###############################################################
#  Generated by:      Cadence Innovus 23.14-s088_1
#  OS:                Linux x86_64(Host ID user1-EliteMini)
#  Generated on:      Wed Aug 12 00:47:21 2026
#  Design:            riscv_pipeline
#  Command:           write_lef_abstract -noCutObs ./outputs/riscv_pipeline.lef
###############################################################

VERSION 5.8 ;

BUSBITCHARS "[]" ;
DIVIDERCHAR "/" ;

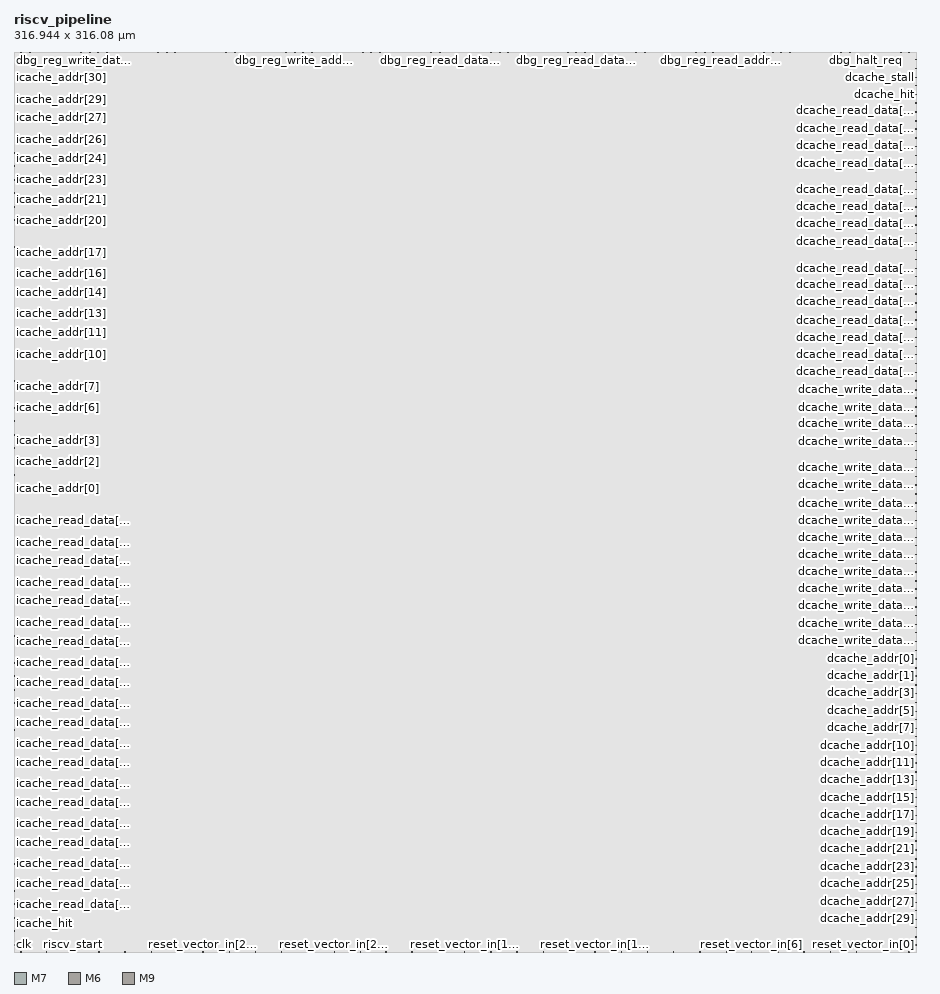
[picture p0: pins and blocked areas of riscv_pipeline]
MACRO riscv_pipeline
  CLASS BLOCK ;
  SIZE 316.944000 BY 316.080000 ;
  FOREIGN riscv_pipeline 0.000000 0.000000 ;
  ORIGIN 0 0 ;
  SYMMETRY X Y R90 ;
  PIN clk
    DIRECTION INPUT ;
    USE SIGNAL ;
    PORT
      LAYER M7 ;
        RECT 2.384000 0.000000 2.512000 0.288000 ;
    END
  END clk
  PIN reset_n
    DIRECTION INPUT ;
    USE SIGNAL ;
    PORT
      LAYER M7 ;
        RECT 11.312000 0.000000 11.440000 0.288000 ;
    END
  END reset_n
  PIN riscv_start
    DIRECTION INPUT ;
    USE SIGNAL ;
    PORT
      LAYER M7 ;
        RECT 20.528000 0.000000 20.656000 0.288000 ;
    END
  END riscv_start
  PIN meip_i
    DIRECTION INPUT ;
    USE SIGNAL ;
    PORT
      LAYER M7 ;
        RECT 314.288000 315.792000 314.416000 316.080000 ;
    END
  END meip_i
  PIN msip_i
    DIRECTION INPUT ;
    USE SIGNAL ;
    PORT
      LAYER M7 ;
        RECT 311.408000 315.792000 311.536000 316.080000 ;
    END
  END msip_i
  PIN mtip_i
    DIRECTION INPUT ;
    USE SIGNAL ;
    PORT
      LAYER M7 ;
        RECT 308.528000 315.792000 308.656000 316.080000 ;
    END
  END mtip_i
  PIN reset_vector_in[31]
    DIRECTION INPUT ;
    USE SIGNAL ;
    PORT
      LAYER M7 ;
        RECT 29.744000 0.000000 29.872000 0.288000 ;
    END
  END reset_vector_in[31]
  PIN reset_vector_in[30]
    DIRECTION INPUT ;
    USE SIGNAL ;
    PORT
      LAYER M7 ;
        RECT 38.960000 0.000000 39.088000 0.288000 ;
    END
  END reset_vector_in[30]
  PIN reset_vector_in[29]
    DIRECTION INPUT ;
    USE SIGNAL ;
    PORT
      LAYER M7 ;
        RECT 48.176000 0.000000 48.304000 0.288000 ;
    END
  END reset_vector_in[29]
  PIN reset_vector_in[28]
    DIRECTION INPUT ;
    USE SIGNAL ;
    PORT
      LAYER M7 ;
        RECT 57.392000 0.000000 57.520000 0.288000 ;
    END
  END reset_vector_in[28]
  PIN reset_vector_in[27]
    DIRECTION INPUT ;
    USE SIGNAL ;
    PORT
      LAYER M7 ;
        RECT 66.320000 0.000000 66.448000 0.288000 ;
    END
  END reset_vector_in[27]
  PIN reset_vector_in[26]
    DIRECTION INPUT ;
    USE SIGNAL ;
    PORT
      LAYER M7 ;
        RECT 75.536000 0.000000 75.664000 0.288000 ;
    END
  END reset_vector_in[26]
  PIN reset_vector_in[25]
    DIRECTION INPUT ;
    USE SIGNAL ;
    PORT
      LAYER M7 ;
        RECT 84.752000 0.000000 84.880000 0.288000 ;
    END
  END reset_vector_in[25]
  PIN reset_vector_in[24]
    DIRECTION INPUT ;
    USE SIGNAL ;
    PORT
      LAYER M7 ;
        RECT 93.968000 0.000000 94.096000 0.288000 ;
    END
  END reset_vector_in[24]
  PIN reset_vector_in[23]
    DIRECTION INPUT ;
    USE SIGNAL ;
    PORT
      LAYER M7 ;
        RECT 103.184000 0.000000 103.312000 0.288000 ;
    END
  END reset_vector_in[23]
  PIN reset_vector_in[22]
    DIRECTION INPUT ;
    USE SIGNAL ;
    PORT
      LAYER M7 ;
        RECT 112.400000 0.000000 112.528000 0.288000 ;
    END
  END reset_vector_in[22]
  PIN reset_vector_in[21]
    DIRECTION INPUT ;
    USE SIGNAL ;
    PORT
      LAYER M7 ;
        RECT 121.616000 0.000000 121.744000 0.288000 ;
    END
  END reset_vector_in[21]
  PIN reset_vector_in[20]
    DIRECTION INPUT ;
    USE SIGNAL ;
    PORT
      LAYER M7 ;
        RECT 130.544000 0.000000 130.672000 0.288000 ;
    END
  END reset_vector_in[20]
  PIN reset_vector_in[19]
    DIRECTION INPUT ;
    USE SIGNAL ;
    PORT
      LAYER M7 ;
        RECT 139.760000 0.000000 139.888000 0.288000 ;
    END
  END reset_vector_in[19]
  PIN reset_vector_in[18]
    DIRECTION INPUT ;
    USE SIGNAL ;
    PORT
      LAYER M7 ;
        RECT 148.976000 0.000000 149.104000 0.288000 ;
    END
  END reset_vector_in[18]
  PIN reset_vector_in[17]
    DIRECTION INPUT ;
    USE SIGNAL ;
    PORT
      LAYER M7 ;
        RECT 158.192000 0.000000 158.320000 0.288000 ;
    END
  END reset_vector_in[17]
  PIN reset_vector_in[16]
    DIRECTION INPUT ;
    USE SIGNAL ;
    PORT
      LAYER M7 ;
        RECT 167.408000 0.000000 167.536000 0.288000 ;
    END
  END reset_vector_in[16]
  PIN reset_vector_in[15]
    DIRECTION INPUT ;
    USE SIGNAL ;
    PORT
      LAYER M7 ;
        RECT 176.624000 0.000000 176.752000 0.288000 ;
    END
  END reset_vector_in[15]
  PIN reset_vector_in[14]
    DIRECTION INPUT ;
    USE SIGNAL ;
    PORT
      LAYER M7 ;
        RECT 185.840000 0.000000 185.968000 0.288000 ;
    END
  END reset_vector_in[14]
  PIN reset_vector_in[13]
    DIRECTION INPUT ;
    USE SIGNAL ;
    PORT
      LAYER M7 ;
        RECT 194.768000 0.000000 194.896000 0.288000 ;
    END
  END reset_vector_in[13]
  PIN reset_vector_in[12]
    DIRECTION INPUT ;
    USE SIGNAL ;
    PORT
      LAYER M7 ;
        RECT 203.984000 0.000000 204.112000 0.288000 ;
    END
  END reset_vector_in[12]
  PIN reset_vector_in[11]
    DIRECTION INPUT ;
    USE SIGNAL ;
    PORT
      LAYER M7 ;
        RECT 213.200000 0.000000 213.328000 0.288000 ;
    END
  END reset_vector_in[11]
  PIN reset_vector_in[10]
    DIRECTION INPUT ;
    USE SIGNAL ;
    PORT
      LAYER M7 ;
        RECT 222.416000 0.000000 222.544000 0.288000 ;
    END
  END reset_vector_in[10]
  PIN reset_vector_in[9]
    DIRECTION INPUT ;
    USE SIGNAL ;
    PORT
      LAYER M7 ;
        RECT 231.632000 0.000000 231.760000 0.288000 ;
    END
  END reset_vector_in[9]
  PIN reset_vector_in[8]
    DIRECTION INPUT ;
    USE SIGNAL ;
    PORT
      LAYER M7 ;
        RECT 240.848000 0.000000 240.976000 0.288000 ;
    END
  END reset_vector_in[8]
  PIN reset_vector_in[7]
    DIRECTION INPUT ;
    USE SIGNAL ;
    PORT
      LAYER M7 ;
        RECT 250.064000 0.000000 250.192000 0.288000 ;
    END
  END reset_vector_in[7]
  PIN reset_vector_in[6]
    DIRECTION INPUT ;
    USE SIGNAL ;
    PORT
      LAYER M7 ;
        RECT 258.992000 0.000000 259.120000 0.288000 ;
    END
  END reset_vector_in[6]
  PIN reset_vector_in[5]
    DIRECTION INPUT ;
    USE SIGNAL ;
    PORT
      LAYER M7 ;
        RECT 268.208000 0.000000 268.336000 0.288000 ;
    END
  END reset_vector_in[5]
  PIN reset_vector_in[4]
    DIRECTION INPUT ;
    USE SIGNAL ;
    PORT
      LAYER M7 ;
        RECT 277.424000 0.000000 277.552000 0.288000 ;
    END
  END reset_vector_in[4]
  PIN reset_vector_in[3]
    DIRECTION INPUT ;
    USE SIGNAL ;
    PORT
      LAYER M7 ;
        RECT 286.640000 0.000000 286.768000 0.288000 ;
    END
  END reset_vector_in[3]
  PIN reset_vector_in[2]
    DIRECTION INPUT ;
    USE SIGNAL ;
    PORT
      LAYER M7 ;
        RECT 295.856000 0.000000 295.984000 0.288000 ;
    END
  END reset_vector_in[2]
  PIN reset_vector_in[1]
    DIRECTION INPUT ;
    USE SIGNAL ;
    PORT
      LAYER M7 ;
        RECT 305.072000 0.000000 305.200000 0.288000 ;
    END
  END reset_vector_in[1]
  PIN reset_vector_in[0]
    DIRECTION INPUT ;
    USE SIGNAL ;
    PORT
      LAYER M7 ;
        RECT 314.288000 0.000000 314.416000 0.288000 ;
    END
  END reset_vector_in[0]
  PIN riscv_done
    DIRECTION OUTPUT ;
    USE SIGNAL ;
    PORT
      LAYER M7 ;
        RECT 305.360000 315.792000 305.488000 316.080000 ;
    END
  END riscv_done
  PIN icache_read_req
    DIRECTION OUTPUT ;
    USE SIGNAL ;
    PORT
      LAYER M6 ;
        RECT 0.000000 313.424000 0.288000 313.552000 ;
    END
  END icache_read_req
  PIN icache_addr[31]
    DIRECTION OUTPUT ;
    USE SIGNAL ;
    PORT
      LAYER M6 ;
        RECT 0.000000 308.816000 0.288000 308.944000 ;
    END
  END icache_addr[31]
  PIN icache_addr[30]
    DIRECTION OUTPUT ;
    USE SIGNAL ;
    PORT
      LAYER M6 ;
        RECT 0.000000 304.208000 0.288000 304.336000 ;
    END
  END icache_addr[30]
  PIN icache_addr[29]
    DIRECTION OUTPUT ;
    USE SIGNAL ;
    PORT
      LAYER M6 ;
        RECT 0.000000 299.312000 0.288000 299.440000 ;
    END
  END icache_addr[29]
  PIN icache_addr[28]
    DIRECTION OUTPUT ;
    USE SIGNAL ;
    PORT
      LAYER M6 ;
        RECT 0.000000 294.704000 0.288000 294.832000 ;
    END
  END icache_addr[28]
  PIN icache_addr[27]
    DIRECTION OUTPUT ;
    USE SIGNAL ;
    PORT
      LAYER M6 ;
        RECT 0.000000 290.096000 0.288000 290.224000 ;
    END
  END icache_addr[27]
  PIN icache_addr[26]
    DIRECTION OUTPUT ;
    USE SIGNAL ;
    PORT
      LAYER M6 ;
        RECT 0.000000 285.200000 0.288000 285.328000 ;
    END
  END icache_addr[26]
  PIN icache_addr[25]
    DIRECTION OUTPUT ;
    USE SIGNAL ;
    PORT
      LAYER M6 ;
        RECT 0.000000 280.592000 0.288000 280.720000 ;
    END
  END icache_addr[25]
  PIN icache_addr[24]
    DIRECTION OUTPUT ;
    USE SIGNAL ;
    PORT
      LAYER M6 ;
        RECT 0.000000 275.984000 0.288000 276.112000 ;
    END
  END icache_addr[24]
  PIN icache_addr[23]
    DIRECTION OUTPUT ;
    USE SIGNAL ;
    PORT
      LAYER M6 ;
        RECT 0.000000 271.088000 0.288000 271.216000 ;
    END
  END icache_addr[23]
  PIN icache_addr[22]
    DIRECTION OUTPUT ;
    USE SIGNAL ;
    PORT
      LAYER M6 ;
        RECT 0.000000 266.480000 0.288000 266.608000 ;
    END
  END icache_addr[22]
  PIN icache_addr[21]
    DIRECTION OUTPUT ;
    USE SIGNAL ;
    PORT
      LAYER M6 ;
        RECT 0.000000 261.584000 0.288000 261.712000 ;
    END
  END icache_addr[21]
  PIN icache_addr[20]
    DIRECTION OUTPUT ;
    USE SIGNAL ;
    PORT
      LAYER M6 ;
        RECT 0.000000 256.976000 0.288000 257.104000 ;
    END
  END icache_addr[20]
  PIN icache_addr[19]
    DIRECTION OUTPUT ;
    USE SIGNAL ;
    PORT
      LAYER M6 ;
        RECT 0.000000 252.368000 0.288000 252.496000 ;
    END
  END icache_addr[19]
  PIN icache_addr[18]
    DIRECTION OUTPUT ;
    USE SIGNAL ;
    PORT
      LAYER M6 ;
        RECT 0.000000 247.472000 0.288000 247.600000 ;
    END
  END icache_addr[18]
  PIN icache_addr[17]
    DIRECTION OUTPUT ;
    USE SIGNAL ;
    PORT
      LAYER M6 ;
        RECT 0.000000 242.864000 0.288000 242.992000 ;
    END
  END icache_addr[17]
  PIN icache_addr[16]
    DIRECTION OUTPUT ;
    USE SIGNAL ;
    PORT
      LAYER M6 ;
        RECT 0.000000 238.256000 0.288000 238.384000 ;
    END
  END icache_addr[16]
  PIN icache_addr[15]
    DIRECTION OUTPUT ;
    USE SIGNAL ;
    PORT
      LAYER M6 ;
        RECT 0.000000 233.360000 0.288000 233.488000 ;
    END
  END icache_addr[15]
  PIN icache_addr[14]
    DIRECTION OUTPUT ;
    USE SIGNAL ;
    PORT
      LAYER M6 ;
        RECT 0.000000 228.752000 0.288000 228.880000 ;
    END
  END icache_addr[14]
  PIN icache_addr[13]
    DIRECTION OUTPUT ;
    USE SIGNAL ;
    PORT
      LAYER M6 ;
        RECT 0.000000 224.144000 0.288000 224.272000 ;
    END
  END icache_addr[13]
  PIN icache_addr[12]
    DIRECTION OUTPUT ;
    USE SIGNAL ;
    PORT
      LAYER M6 ;
        RECT 0.000000 219.248000 0.288000 219.376000 ;
    END
  END icache_addr[12]
  PIN icache_addr[11]
    DIRECTION OUTPUT ;
    USE SIGNAL ;
    PORT
      LAYER M6 ;
        RECT 0.000000 214.640000 0.288000 214.768000 ;
    END
  END icache_addr[11]
  PIN icache_addr[10]
    DIRECTION OUTPUT ;
    USE SIGNAL ;
    PORT
      LAYER M6 ;
        RECT 0.000000 209.744000 0.288000 209.872000 ;
    END
  END icache_addr[10]
  PIN icache_addr[9]
    DIRECTION OUTPUT ;
    USE SIGNAL ;
    PORT
      LAYER M6 ;
        RECT 0.000000 205.136000 0.288000 205.264000 ;
    END
  END icache_addr[9]
  PIN icache_addr[8]
    DIRECTION OUTPUT ;
    USE SIGNAL ;
    PORT
      LAYER M6 ;
        RECT 0.000000 200.528000 0.288000 200.656000 ;
    END
  END icache_addr[8]
  PIN icache_addr[7]
    DIRECTION OUTPUT ;
    USE SIGNAL ;
    PORT
      LAYER M6 ;
        RECT 0.000000 195.632000 0.288000 195.760000 ;
    END
  END icache_addr[7]
  PIN icache_addr[6]
    DIRECTION OUTPUT ;
    USE SIGNAL ;
    PORT
      LAYER M6 ;
        RECT 0.000000 191.024000 0.288000 191.152000 ;
    END
  END icache_addr[6]
  PIN icache_addr[5]
    DIRECTION OUTPUT ;
    USE SIGNAL ;
    PORT
      LAYER M6 ;
        RECT 0.000000 186.416000 0.288000 186.544000 ;
    END
  END icache_addr[5]
  PIN icache_addr[4]
    DIRECTION OUTPUT ;
    USE SIGNAL ;
    PORT
      LAYER M6 ;
        RECT 0.000000 181.520000 0.288000 181.648000 ;
    END
  END icache_addr[4]
  PIN icache_addr[3]
    DIRECTION OUTPUT ;
    USE SIGNAL ;
    PORT
      LAYER M6 ;
        RECT 0.000000 176.912000 0.288000 177.040000 ;
    END
  END icache_addr[3]
  PIN icache_addr[2]
    DIRECTION OUTPUT ;
    USE SIGNAL ;
    PORT
      LAYER M6 ;
        RECT 0.000000 172.304000 0.288000 172.432000 ;
    END
  END icache_addr[2]
  PIN icache_addr[1]
    DIRECTION OUTPUT ;
    USE SIGNAL ;
    PORT
      LAYER M6 ;
        RECT 0.000000 167.408000 0.288000 167.536000 ;
    END
  END icache_addr[1]
  PIN icache_addr[0]
    DIRECTION OUTPUT ;
    USE SIGNAL ;
    PORT
      LAYER M6 ;
        RECT 0.000000 162.800000 0.288000 162.928000 ;
    END
  END icache_addr[0]
  PIN icache_read_data[31]
    DIRECTION INPUT ;
    USE SIGNAL ;
    PORT
      LAYER M6 ;
        RECT 0.000000 157.904000 0.288000 158.032000 ;
    END
  END icache_read_data[31]
  PIN icache_read_data[30]
    DIRECTION INPUT ;
    USE SIGNAL ;
    PORT
      LAYER M6 ;
        RECT 0.000000 153.296000 0.288000 153.424000 ;
    END
  END icache_read_data[30]
  PIN icache_read_data[29]
    DIRECTION INPUT ;
    USE SIGNAL ;
    PORT
      LAYER M6 ;
        RECT 0.000000 148.688000 0.288000 148.816000 ;
    END
  END icache_read_data[29]
  PIN icache_read_data[28]
    DIRECTION INPUT ;
    USE SIGNAL ;
    PORT
      LAYER M6 ;
        RECT 0.000000 143.792000 0.288000 143.920000 ;
    END
  END icache_read_data[28]
  PIN icache_read_data[27]
    DIRECTION INPUT ;
    USE SIGNAL ;
    PORT
      LAYER M6 ;
        RECT 0.000000 139.184000 0.288000 139.312000 ;
    END
  END icache_read_data[27]
  PIN icache_read_data[26]
    DIRECTION INPUT ;
    USE SIGNAL ;
    PORT
      LAYER M6 ;
        RECT 0.000000 134.576000 0.288000 134.704000 ;
    END
  END icache_read_data[26]
  PIN icache_read_data[25]
    DIRECTION INPUT ;
    USE SIGNAL ;
    PORT
      LAYER M6 ;
        RECT 0.000000 129.680000 0.288000 129.808000 ;
    END
  END icache_read_data[25]
  PIN icache_read_data[24]
    DIRECTION INPUT ;
    USE SIGNAL ;
    PORT
      LAYER M6 ;
        RECT 0.000000 125.072000 0.288000 125.200000 ;
    END
  END icache_read_data[24]
  PIN icache_read_data[23]
    DIRECTION INPUT ;
    USE SIGNAL ;
    PORT
      LAYER M6 ;
        RECT 0.000000 120.464000 0.288000 120.592000 ;
    END
  END icache_read_data[23]
  PIN icache_read_data[22]
    DIRECTION INPUT ;
    USE SIGNAL ;
    PORT
      LAYER M6 ;
        RECT 0.000000 115.568000 0.288000 115.696000 ;
    END
  END icache_read_data[22]
  PIN icache_read_data[21]
    DIRECTION INPUT ;
    USE SIGNAL ;
    PORT
      LAYER M6 ;
        RECT 0.000000 110.960000 0.288000 111.088000 ;
    END
  END icache_read_data[21]
  PIN icache_read_data[20]
    DIRECTION INPUT ;
    USE SIGNAL ;
    PORT
      LAYER M6 ;
        RECT 0.000000 106.064000 0.288000 106.192000 ;
    END
  END icache_read_data[20]
  PIN icache_read_data[19]
    DIRECTION INPUT ;
    USE SIGNAL ;
    PORT
      LAYER M6 ;
        RECT 0.000000 101.456000 0.288000 101.584000 ;
    END
  END icache_read_data[19]
  PIN icache_read_data[18]
    DIRECTION INPUT ;
    USE SIGNAL ;
    PORT
      LAYER M6 ;
        RECT 0.000000 96.848000 0.288000 96.976000 ;
    END
  END icache_read_data[18]
  PIN icache_read_data[17]
    DIRECTION INPUT ;
    USE SIGNAL ;
    PORT
      LAYER M6 ;
        RECT 0.000000 91.952000 0.288000 92.080000 ;
    END
  END icache_read_data[17]
  PIN icache_read_data[16]
    DIRECTION INPUT ;
    USE SIGNAL ;
    PORT
      LAYER M6 ;
        RECT 0.000000 87.344000 0.288000 87.472000 ;
    END
  END icache_read_data[16]
  PIN icache_read_data[15]
    DIRECTION INPUT ;
    USE SIGNAL ;
    PORT
      LAYER M6 ;
        RECT 0.000000 82.736000 0.288000 82.864000 ;
    END
  END icache_read_data[15]
  PIN icache_read_data[14]
    DIRECTION INPUT ;
    USE SIGNAL ;
    PORT
      LAYER M6 ;
        RECT 0.000000 77.840000 0.288000 77.968000 ;
    END
  END icache_read_data[14]
  PIN icache_read_data[13]
    DIRECTION INPUT ;
    USE SIGNAL ;
    PORT
      LAYER M6 ;
        RECT 0.000000 73.232000 0.288000 73.360000 ;
    END
  END icache_read_data[13]
  PIN icache_read_data[12]
    DIRECTION INPUT ;
    USE SIGNAL ;
    PORT
      LAYER M6 ;
        RECT 0.000000 68.624000 0.288000 68.752000 ;
    END
  END icache_read_data[12]
  PIN icache_read_data[11]
    DIRECTION INPUT ;
    USE SIGNAL ;
    PORT
      LAYER M6 ;
        RECT 0.000000 63.728000 0.288000 63.856000 ;
    END
  END icache_read_data[11]
  PIN icache_read_data[10]
    DIRECTION INPUT ;
    USE SIGNAL ;
    PORT
      LAYER M6 ;
        RECT 0.000000 59.120000 0.288000 59.248000 ;
    END
  END icache_read_data[10]
  PIN icache_read_data[9]
    DIRECTION INPUT ;
    USE SIGNAL ;
    PORT
      LAYER M6 ;
        RECT 0.000000 54.224000 0.288000 54.352000 ;
    END
  END icache_read_data[9]
  PIN icache_read_data[8]
    DIRECTION INPUT ;
    USE SIGNAL ;
    PORT
      LAYER M6 ;
        RECT 0.000000 49.616000 0.288000 49.744000 ;
    END
  END icache_read_data[8]
  PIN icache_read_data[7]
    DIRECTION INPUT ;
    USE SIGNAL ;
    PORT
      LAYER M6 ;
        RECT 0.000000 45.008000 0.288000 45.136000 ;
    END
  END icache_read_data[7]
  PIN icache_read_data[6]
    DIRECTION INPUT ;
    USE SIGNAL ;
    PORT
      LAYER M6 ;
        RECT 0.000000 40.112000 0.288000 40.240000 ;
    END
  END icache_read_data[6]
  PIN icache_read_data[5]
    DIRECTION INPUT ;
    USE SIGNAL ;
    PORT
      LAYER M6 ;
        RECT 0.000000 35.504000 0.288000 35.632000 ;
    END
  END icache_read_data[5]
  PIN icache_read_data[4]
    DIRECTION INPUT ;
    USE SIGNAL ;
    PORT
      LAYER M6 ;
        RECT 0.000000 30.896000 0.288000 31.024000 ;
    END
  END icache_read_data[4]
  PIN icache_read_data[3]
    DIRECTION INPUT ;
    USE SIGNAL ;
    PORT
      LAYER M6 ;
        RECT 0.000000 26.000000 0.288000 26.128000 ;
    END
  END icache_read_data[3]
  PIN icache_read_data[2]
    DIRECTION INPUT ;
    USE SIGNAL ;
    PORT
      LAYER M6 ;
        RECT 0.000000 21.392000 0.288000 21.520000 ;
    END
  END icache_read_data[2]
  PIN icache_read_data[1]
    DIRECTION INPUT ;
    USE SIGNAL ;
    PORT
      LAYER M6 ;
        RECT 0.000000 16.784000 0.288000 16.912000 ;
    END
  END icache_read_data[1]
  PIN icache_read_data[0]
    DIRECTION INPUT ;
    USE SIGNAL ;
    PORT
      LAYER M6 ;
        RECT 0.000000 11.888000 0.288000 12.016000 ;
    END
  END icache_read_data[0]
  PIN icache_hit
    DIRECTION INPUT ;
    USE SIGNAL ;
    PORT
      LAYER M6 ;
        RECT 0.000000 7.280000 0.288000 7.408000 ;
    END
  END icache_hit
  PIN icache_stall
    DIRECTION INPUT ;
    USE SIGNAL ;
    PORT
      LAYER M6 ;
        RECT 0.000000 2.384000 0.288000 2.512000 ;
    END
  END icache_stall
  PIN dcache_read_req
    DIRECTION OUTPUT ;
    USE SIGNAL ;
    PORT
      LAYER M6 ;
        RECT 316.656000 2.384000 316.944000 2.512000 ;
    END
  END dcache_read_req
  PIN dcache_write_req
    DIRECTION OUTPUT ;
    USE SIGNAL ;
    PORT
      LAYER M6 ;
        RECT 316.656000 5.264000 316.944000 5.392000 ;
    END
  END dcache_write_req
  PIN dcache_addr[31]
    DIRECTION OUTPUT ;
    USE SIGNAL ;
    PORT
      LAYER M6 ;
        RECT 316.656000 8.432000 316.944000 8.560000 ;
    END
  END dcache_addr[31]
  PIN dcache_addr[30]
    DIRECTION OUTPUT ;
    USE SIGNAL ;
    PORT
      LAYER M6 ;
        RECT 316.656000 11.312000 316.944000 11.440000 ;
    END
  END dcache_addr[30]
  PIN dcache_addr[29]
    DIRECTION OUTPUT ;
    USE SIGNAL ;
    PORT
      LAYER M6 ;
        RECT 316.656000 14.480000 316.944000 14.608000 ;
    END
  END dcache_addr[29]
  PIN dcache_addr[28]
    DIRECTION OUTPUT ;
    USE SIGNAL ;
    PORT
      LAYER M6 ;
        RECT 316.656000 17.360000 316.944000 17.488000 ;
    END
  END dcache_addr[28]
  PIN dcache_addr[27]
    DIRECTION OUTPUT ;
    USE SIGNAL ;
    PORT
      LAYER M6 ;
        RECT 316.656000 20.528000 316.944000 20.656000 ;
    END
  END dcache_addr[27]
  PIN dcache_addr[26]
    DIRECTION OUTPUT ;
    USE SIGNAL ;
    PORT
      LAYER M6 ;
        RECT 316.656000 23.696000 316.944000 23.824000 ;
    END
  END dcache_addr[26]
  PIN dcache_addr[25]
    DIRECTION OUTPUT ;
    USE SIGNAL ;
    PORT
      LAYER M6 ;
        RECT 316.656000 26.576000 316.944000 26.704000 ;
    END
  END dcache_addr[25]
  PIN dcache_addr[24]
    DIRECTION OUTPUT ;
    USE SIGNAL ;
    PORT
      LAYER M6 ;
        RECT 316.656000 29.744000 316.944000 29.872000 ;
    END
  END dcache_addr[24]
  PIN dcache_addr[23]
    DIRECTION OUTPUT ;
    USE SIGNAL ;
    PORT
      LAYER M6 ;
        RECT 316.656000 32.624000 316.944000 32.752000 ;
    END
  END dcache_addr[23]
  PIN dcache_addr[22]
    DIRECTION OUTPUT ;
    USE SIGNAL ;
    PORT
      LAYER M6 ;
        RECT 316.656000 35.792000 316.944000 35.920000 ;
    END
  END dcache_addr[22]
  PIN dcache_addr[21]
    DIRECTION OUTPUT ;
    USE SIGNAL ;
    PORT
      LAYER M6 ;
        RECT 316.656000 38.960000 316.944000 39.088000 ;
    END
  END dcache_addr[21]
  PIN dcache_addr[20]
    DIRECTION OUTPUT ;
    USE SIGNAL ;
    PORT
      LAYER M6 ;
        RECT 316.656000 41.840000 316.944000 41.968000 ;
    END
  END dcache_addr[20]
  PIN dcache_addr[19]
    DIRECTION OUTPUT ;
    USE SIGNAL ;
    PORT
      LAYER M6 ;
        RECT 316.656000 45.008000 316.944000 45.136000 ;
    END
  END dcache_addr[19]
  PIN dcache_addr[18]
    DIRECTION OUTPUT ;
    USE SIGNAL ;
    PORT
      LAYER M6 ;
        RECT 316.656000 47.888000 316.944000 48.016000 ;
    END
  END dcache_addr[18]
  PIN dcache_addr[17]
    DIRECTION OUTPUT ;
    USE SIGNAL ;
    PORT
      LAYER M6 ;
        RECT 316.656000 51.056000 316.944000 51.184000 ;
    END
  END dcache_addr[17]
  PIN dcache_addr[16]
    DIRECTION OUTPUT ;
    USE SIGNAL ;
    PORT
      LAYER M6 ;
        RECT 316.656000 54.224000 316.944000 54.352000 ;
    END
  END dcache_addr[16]
  PIN dcache_addr[15]
    DIRECTION OUTPUT ;
    USE SIGNAL ;
    PORT
      LAYER M6 ;
        RECT 316.656000 57.104000 316.944000 57.232000 ;
    END
  END dcache_addr[15]
  PIN dcache_addr[14]
    DIRECTION OUTPUT ;
    USE SIGNAL ;
    PORT
      LAYER M6 ;
        RECT 316.656000 60.272000 316.944000 60.400000 ;
    END
  END dcache_addr[14]
  PIN dcache_addr[13]
    DIRECTION OUTPUT ;
    USE SIGNAL ;
    PORT
      LAYER M6 ;
        RECT 316.656000 63.152000 316.944000 63.280000 ;
    END
  END dcache_addr[13]
  PIN dcache_addr[12]
    DIRECTION OUTPUT ;
    USE SIGNAL ;
    PORT
      LAYER M6 ;
        RECT 316.656000 66.320000 316.944000 66.448000 ;
    END
  END dcache_addr[12]
  PIN dcache_addr[11]
    DIRECTION OUTPUT ;
    USE SIGNAL ;
    PORT
      LAYER M6 ;
        RECT 316.656000 69.200000 316.944000 69.328000 ;
    END
  END dcache_addr[11]
  PIN dcache_addr[10]
    DIRECTION OUTPUT ;
    USE SIGNAL ;
    PORT
      LAYER M6 ;
        RECT 316.656000 72.368000 316.944000 72.496000 ;
    END
  END dcache_addr[10]
  PIN dcache_addr[9]
    DIRECTION OUTPUT ;
    USE SIGNAL ;
    PORT
      LAYER M6 ;
        RECT 316.656000 75.536000 316.944000 75.664000 ;
    END
  END dcache_addr[9]
  PIN dcache_addr[8]
    DIRECTION OUTPUT ;
    USE SIGNAL ;
    PORT
      LAYER M6 ;
        RECT 316.656000 78.416000 316.944000 78.544000 ;
    END
  END dcache_addr[8]
  PIN dcache_addr[7]
    DIRECTION OUTPUT ;
    USE SIGNAL ;
    PORT
      LAYER M6 ;
        RECT 316.656000 81.584000 316.944000 81.712000 ;
    END
  END dcache_addr[7]
  PIN dcache_addr[6]
    DIRECTION OUTPUT ;
    USE SIGNAL ;
    PORT
      LAYER M6 ;
        RECT 316.656000 84.464000 316.944000 84.592000 ;
    END
  END dcache_addr[6]
  PIN dcache_addr[5]
    DIRECTION OUTPUT ;
    USE SIGNAL ;
    PORT
      LAYER M6 ;
        RECT 316.656000 87.632000 316.944000 87.760000 ;
    END
  END dcache_addr[5]
  PIN dcache_addr[4]
    DIRECTION OUTPUT ;
    USE SIGNAL ;
    PORT
      LAYER M6 ;
        RECT 316.656000 90.800000 316.944000 90.928000 ;
    END
  END dcache_addr[4]
  PIN dcache_addr[3]
    DIRECTION OUTPUT ;
    USE SIGNAL ;
    PORT
      LAYER M6 ;
        RECT 316.656000 93.680000 316.944000 93.808000 ;
    END
  END dcache_addr[3]
  PIN dcache_addr[2]
    DIRECTION OUTPUT ;
    USE SIGNAL ;
    PORT
      LAYER M6 ;
        RECT 316.656000 96.848000 316.944000 96.976000 ;
    END
  END dcache_addr[2]
  PIN dcache_addr[1]
    DIRECTION OUTPUT ;
    USE SIGNAL ;
    PORT
      LAYER M6 ;
        RECT 316.656000 99.728000 316.944000 99.856000 ;
    END
  END dcache_addr[1]
  PIN dcache_addr[0]
    DIRECTION OUTPUT ;
    USE SIGNAL ;
    PORT
      LAYER M6 ;
        RECT 316.656000 102.896000 316.944000 103.024000 ;
    END
  END dcache_addr[0]
  PIN dcache_write_data[31]
    DIRECTION OUTPUT ;
    USE SIGNAL ;
    PORT
      LAYER M6 ;
        RECT 316.656000 105.776000 316.944000 105.904000 ;
    END
  END dcache_write_data[31]
  PIN dcache_write_data[30]
    DIRECTION OUTPUT ;
    USE SIGNAL ;
    PORT
      LAYER M6 ;
        RECT 316.656000 108.944000 316.944000 109.072000 ;
    END
  END dcache_write_data[30]
  PIN dcache_write_data[29]
    DIRECTION OUTPUT ;
    USE SIGNAL ;
    PORT
      LAYER M6 ;
        RECT 316.656000 112.112000 316.944000 112.240000 ;
    END
  END dcache_write_data[29]
  PIN dcache_write_data[28]
    DIRECTION OUTPUT ;
    USE SIGNAL ;
    PORT
      LAYER M6 ;
        RECT 316.656000 114.992000 316.944000 115.120000 ;
    END
  END dcache_write_data[28]
  PIN dcache_write_data[27]
    DIRECTION OUTPUT ;
    USE SIGNAL ;
    PORT
      LAYER M6 ;
        RECT 316.656000 118.160000 316.944000 118.288000 ;
    END
  END dcache_write_data[27]
  PIN dcache_write_data[26]
    DIRECTION OUTPUT ;
    USE SIGNAL ;
    PORT
      LAYER M6 ;
        RECT 316.656000 121.040000 316.944000 121.168000 ;
    END
  END dcache_write_data[26]
  PIN dcache_write_data[25]
    DIRECTION OUTPUT ;
    USE SIGNAL ;
    PORT
      LAYER M6 ;
        RECT 316.656000 124.208000 316.944000 124.336000 ;
    END
  END dcache_write_data[25]
  PIN dcache_write_data[24]
    DIRECTION OUTPUT ;
    USE SIGNAL ;
    PORT
      LAYER M6 ;
        RECT 316.656000 127.376000 316.944000 127.504000 ;
    END
  END dcache_write_data[24]
  PIN dcache_write_data[23]
    DIRECTION OUTPUT ;
    USE SIGNAL ;
    PORT
      LAYER M6 ;
        RECT 316.656000 130.256000 316.944000 130.384000 ;
    END
  END dcache_write_data[23]
  PIN dcache_write_data[22]
    DIRECTION OUTPUT ;
    USE SIGNAL ;
    PORT
      LAYER M6 ;
        RECT 316.656000 133.424000 316.944000 133.552000 ;
    END
  END dcache_write_data[22]
  PIN dcache_write_data[21]
    DIRECTION OUTPUT ;
    USE SIGNAL ;
    PORT
      LAYER M6 ;
        RECT 316.656000 136.304000 316.944000 136.432000 ;
    END
  END dcache_write_data[21]
  PIN dcache_write_data[20]
    DIRECTION OUTPUT ;
    USE SIGNAL ;
    PORT
      LAYER M6 ;
        RECT 316.656000 139.472000 316.944000 139.600000 ;
    END
  END dcache_write_data[20]
  PIN dcache_write_data[19]
    DIRECTION OUTPUT ;
    USE SIGNAL ;
    PORT
      LAYER M6 ;
        RECT 316.656000 142.640000 316.944000 142.768000 ;
    END
  END dcache_write_data[19]
  PIN dcache_write_data[18]
    DIRECTION OUTPUT ;
    USE SIGNAL ;
    PORT
      LAYER M6 ;
        RECT 316.656000 145.520000 316.944000 145.648000 ;
    END
  END dcache_write_data[18]
  PIN dcache_write_data[17]
    DIRECTION OUTPUT ;
    USE SIGNAL ;
    PORT
      LAYER M6 ;
        RECT 316.656000 148.688000 316.944000 148.816000 ;
    END
  END dcache_write_data[17]
  PIN dcache_write_data[16]
    DIRECTION OUTPUT ;
    USE SIGNAL ;
    PORT
      LAYER M6 ;
        RECT 316.656000 151.568000 316.944000 151.696000 ;
    END
  END dcache_write_data[16]
  PIN dcache_write_data[15]
    DIRECTION OUTPUT ;
    USE SIGNAL ;
    PORT
      LAYER M6 ;
        RECT 316.656000 154.736000 316.944000 154.864000 ;
    END
  END dcache_write_data[15]
  PIN dcache_write_data[14]
    DIRECTION OUTPUT ;
    USE SIGNAL ;
    PORT
      LAYER M6 ;
        RECT 316.656000 157.616000 316.944000 157.744000 ;
    END
  END dcache_write_data[14]
  PIN dcache_write_data[13]
    DIRECTION OUTPUT ;
    USE SIGNAL ;
    PORT
      LAYER M6 ;
        RECT 316.656000 160.784000 316.944000 160.912000 ;
    END
  END dcache_write_data[13]
  PIN dcache_write_data[12]
    DIRECTION OUTPUT ;
    USE SIGNAL ;
    PORT
      LAYER M6 ;
        RECT 316.656000 163.952000 316.944000 164.080000 ;
    END
  END dcache_write_data[12]
  PIN dcache_write_data[11]
    DIRECTION OUTPUT ;
    USE SIGNAL ;
    PORT
      LAYER M6 ;
        RECT 316.656000 166.832000 316.944000 166.960000 ;
    END
  END dcache_write_data[11]
  PIN dcache_write_data[10]
    DIRECTION OUTPUT ;
    USE SIGNAL ;
    PORT
      LAYER M6 ;
        RECT 316.656000 170.000000 316.944000 170.128000 ;
    END
  END dcache_write_data[10]
  PIN dcache_write_data[9]
    DIRECTION OUTPUT ;
    USE SIGNAL ;
    PORT
      LAYER M6 ;
        RECT 316.656000 172.880000 316.944000 173.008000 ;
    END
  END dcache_write_data[9]
  PIN dcache_write_data[8]
    DIRECTION OUTPUT ;
    USE SIGNAL ;
    PORT
      LAYER M6 ;
        RECT 316.656000 176.048000 316.944000 176.176000 ;
    END
  END dcache_write_data[8]
  PIN dcache_write_data[7]
    DIRECTION OUTPUT ;
    USE SIGNAL ;
    PORT
      LAYER M6 ;
        RECT 316.656000 179.216000 316.944000 179.344000 ;
    END
  END dcache_write_data[7]
  PIN dcache_write_data[6]
    DIRECTION OUTPUT ;
    USE SIGNAL ;
    PORT
      LAYER M6 ;
        RECT 316.656000 182.096000 316.944000 182.224000 ;
    END
  END dcache_write_data[6]
  PIN dcache_write_data[5]
    DIRECTION OUTPUT ;
    USE SIGNAL ;
    PORT
      LAYER M6 ;
        RECT 316.656000 185.264000 316.944000 185.392000 ;
    END
  END dcache_write_data[5]
  PIN dcache_write_data[4]
    DIRECTION OUTPUT ;
    USE SIGNAL ;
    PORT
      LAYER M6 ;
        RECT 316.656000 188.144000 316.944000 188.272000 ;
    END
  END dcache_write_data[4]
  PIN dcache_write_data[3]
    DIRECTION OUTPUT ;
    USE SIGNAL ;
    PORT
      LAYER M6 ;
        RECT 316.656000 191.312000 316.944000 191.440000 ;
    END
  END dcache_write_data[3]
  PIN dcache_write_data[2]
    DIRECTION OUTPUT ;
    USE SIGNAL ;
    PORT
      LAYER M6 ;
        RECT 316.656000 194.480000 316.944000 194.608000 ;
    END
  END dcache_write_data[2]
  PIN dcache_write_data[1]
    DIRECTION OUTPUT ;
    USE SIGNAL ;
    PORT
      LAYER M6 ;
        RECT 316.656000 197.360000 316.944000 197.488000 ;
    END
  END dcache_write_data[1]
  PIN dcache_write_data[0]
    DIRECTION OUTPUT ;
    USE SIGNAL ;
    PORT
      LAYER M6 ;
        RECT 316.656000 200.528000 316.944000 200.656000 ;
    END
  END dcache_write_data[0]
  PIN dcache_read_data[31]
    DIRECTION INPUT ;
    USE SIGNAL ;
    PORT
      LAYER M6 ;
        RECT 316.656000 203.408000 316.944000 203.536000 ;
    END
  END dcache_read_data[31]
  PIN dcache_read_data[30]
    DIRECTION INPUT ;
    USE SIGNAL ;
    PORT
      LAYER M6 ;
        RECT 316.656000 206.576000 316.944000 206.704000 ;
    END
  END dcache_read_data[30]
  PIN dcache_read_data[29]
    DIRECTION INPUT ;
    USE SIGNAL ;
    PORT
      LAYER M6 ;
        RECT 316.656000 209.744000 316.944000 209.872000 ;
    END
  END dcache_read_data[29]
  PIN dcache_read_data[28]
    DIRECTION INPUT ;
    USE SIGNAL ;
    PORT
      LAYER M6 ;
        RECT 316.656000 212.624000 316.944000 212.752000 ;
    END
  END dcache_read_data[28]
  PIN dcache_read_data[27]
    DIRECTION INPUT ;
    USE SIGNAL ;
    PORT
      LAYER M6 ;
        RECT 316.656000 215.792000 316.944000 215.920000 ;
    END
  END dcache_read_data[27]
  PIN dcache_read_data[26]
    DIRECTION INPUT ;
    USE SIGNAL ;
    PORT
      LAYER M6 ;
        RECT 316.656000 218.672000 316.944000 218.800000 ;
    END
  END dcache_read_data[26]
  PIN dcache_read_data[25]
    DIRECTION INPUT ;
    USE SIGNAL ;
    PORT
      LAYER M6 ;
        RECT 316.656000 221.840000 316.944000 221.968000 ;
    END
  END dcache_read_data[25]
  PIN dcache_read_data[24]
    DIRECTION INPUT ;
    USE SIGNAL ;
    PORT
      LAYER M6 ;
        RECT 316.656000 224.720000 316.944000 224.848000 ;
    END
  END dcache_read_data[24]
  PIN dcache_read_data[23]
    DIRECTION INPUT ;
    USE SIGNAL ;
    PORT
      LAYER M6 ;
        RECT 316.656000 227.888000 316.944000 228.016000 ;
    END
  END dcache_read_data[23]
  PIN dcache_read_data[22]
    DIRECTION INPUT ;
    USE SIGNAL ;
    PORT
      LAYER M6 ;
        RECT 316.656000 231.056000 316.944000 231.184000 ;
    END
  END dcache_read_data[22]
  PIN dcache_read_data[21]
    DIRECTION INPUT ;
    USE SIGNAL ;
    PORT
      LAYER M6 ;
        RECT 316.656000 233.936000 316.944000 234.064000 ;
    END
  END dcache_read_data[21]
  PIN dcache_read_data[20]
    DIRECTION INPUT ;
    USE SIGNAL ;
    PORT
      LAYER M6 ;
        RECT 316.656000 237.104000 316.944000 237.232000 ;
    END
  END dcache_read_data[20]
  PIN dcache_read_data[19]
    DIRECTION INPUT ;
    USE SIGNAL ;
    PORT
      LAYER M6 ;
        RECT 316.656000 239.984000 316.944000 240.112000 ;
    END
  END dcache_read_data[19]
  PIN dcache_read_data[18]
    DIRECTION INPUT ;
    USE SIGNAL ;
    PORT
      LAYER M6 ;
        RECT 316.656000 243.152000 316.944000 243.280000 ;
    END
  END dcache_read_data[18]
  PIN dcache_read_data[17]
    DIRECTION INPUT ;
    USE SIGNAL ;
    PORT
      LAYER M6 ;
        RECT 316.656000 246.320000 316.944000 246.448000 ;
    END
  END dcache_read_data[17]
  PIN dcache_read_data[16]
    DIRECTION INPUT ;
    USE SIGNAL ;
    PORT
      LAYER M6 ;
        RECT 316.656000 249.200000 316.944000 249.328000 ;
    END
  END dcache_read_data[16]
  PIN dcache_read_data[15]
    DIRECTION INPUT ;
    USE SIGNAL ;
    PORT
      LAYER M6 ;
        RECT 316.656000 252.368000 316.944000 252.496000 ;
    END
  END dcache_read_data[15]
  PIN dcache_read_data[14]
    DIRECTION INPUT ;
    USE SIGNAL ;
    PORT
      LAYER M6 ;
        RECT 316.656000 255.248000 316.944000 255.376000 ;
    END
  END dcache_read_data[14]
  PIN dcache_read_data[13]
    DIRECTION INPUT ;
    USE SIGNAL ;
    PORT
      LAYER M6 ;
        RECT 316.656000 258.416000 316.944000 258.544000 ;
    END
  END dcache_read_data[13]
  PIN dcache_read_data[12]
    DIRECTION INPUT ;
    USE SIGNAL ;
    PORT
      LAYER M6 ;
        RECT 316.656000 261.584000 316.944000 261.712000 ;
    END
  END dcache_read_data[12]
  PIN dcache_read_data[11]
    DIRECTION INPUT ;
    USE SIGNAL ;
    PORT
      LAYER M6 ;
        RECT 316.656000 264.464000 316.944000 264.592000 ;
    END
  END dcache_read_data[11]
  PIN dcache_read_data[10]
    DIRECTION INPUT ;
    USE SIGNAL ;
    PORT
      LAYER M6 ;
        RECT 316.656000 267.632000 316.944000 267.760000 ;
    END
  END dcache_read_data[10]
  PIN dcache_read_data[9]
    DIRECTION INPUT ;
    USE SIGNAL ;
    PORT
      LAYER M6 ;
        RECT 316.656000 270.512000 316.944000 270.640000 ;
    END
  END dcache_read_data[9]
  PIN dcache_read_data[8]
    DIRECTION INPUT ;
    USE SIGNAL ;
    PORT
      LAYER M6 ;
        RECT 316.656000 273.680000 316.944000 273.808000 ;
    END
  END dcache_read_data[8]
  PIN dcache_read_data[7]
    DIRECTION INPUT ;
    USE SIGNAL ;
    PORT
      LAYER M6 ;
        RECT 316.656000 276.560000 316.944000 276.688000 ;
    END
  END dcache_read_data[7]
  PIN dcache_read_data[6]
    DIRECTION INPUT ;
    USE SIGNAL ;
    PORT
      LAYER M6 ;
        RECT 316.656000 279.728000 316.944000 279.856000 ;
    END
  END dcache_read_data[6]
  PIN dcache_read_data[5]
    DIRECTION INPUT ;
    USE SIGNAL ;
    PORT
      LAYER M6 ;
        RECT 316.656000 282.896000 316.944000 283.024000 ;
    END
  END dcache_read_data[5]
  PIN dcache_read_data[4]
    DIRECTION INPUT ;
    USE SIGNAL ;
    PORT
      LAYER M6 ;
        RECT 316.656000 285.776000 316.944000 285.904000 ;
    END
  END dcache_read_data[4]
  PIN dcache_read_data[3]
    DIRECTION INPUT ;
    USE SIGNAL ;
    PORT
      LAYER M6 ;
        RECT 316.656000 288.944000 316.944000 289.072000 ;
    END
  END dcache_read_data[3]
  PIN dcache_read_data[2]
    DIRECTION INPUT ;
    USE SIGNAL ;
    PORT
      LAYER M6 ;
        RECT 316.656000 291.824000 316.944000 291.952000 ;
    END
  END dcache_read_data[2]
  PIN dcache_read_data[1]
    DIRECTION INPUT ;
    USE SIGNAL ;
    PORT
      LAYER M6 ;
        RECT 316.656000 294.992000 316.944000 295.120000 ;
    END
  END dcache_read_data[1]
  PIN dcache_read_data[0]
    DIRECTION INPUT ;
    USE SIGNAL ;
    PORT
      LAYER M6 ;
        RECT 316.656000 298.160000 316.944000 298.288000 ;
    END
  END dcache_read_data[0]
  PIN dcache_hit
    DIRECTION INPUT ;
    USE SIGNAL ;
    PORT
      LAYER M6 ;
        RECT 316.656000 301.040000 316.944000 301.168000 ;
    END
  END dcache_hit
  PIN dcache_stall
    DIRECTION INPUT ;
    USE SIGNAL ;
    PORT
      LAYER M6 ;
        RECT 316.656000 304.208000 316.944000 304.336000 ;
    END
  END dcache_stall
  PIN mem_size_top[1]
    DIRECTION OUTPUT ;
    USE SIGNAL ;
    PORT
      LAYER M6 ;
        RECT 316.656000 307.088000 316.944000 307.216000 ;
    END
  END mem_size_top[1]
  PIN mem_size_top[0]
    DIRECTION OUTPUT ;
    USE SIGNAL ;
    PORT
      LAYER M6 ;
        RECT 316.656000 310.256000 316.944000 310.384000 ;
    END
  END mem_size_top[0]
  PIN mem_unsigned_top
    DIRECTION OUTPUT ;
    USE SIGNAL ;
    PORT
      LAYER M6 ;
        RECT 316.656000 313.424000 316.944000 313.552000 ;
    END
  END mem_unsigned_top
  PIN wfi_sleep_out
    DIRECTION OUTPUT ;
    USE SIGNAL ;
    PORT
      LAYER M7 ;
        RECT 302.480000 315.792000 302.608000 316.080000 ;
    END
  END wfi_sleep_out
  PIN dbg_halt_req
    DIRECTION INPUT ;
    USE SIGNAL ;
    PORT
      LAYER M7 ;
        RECT 299.312000 315.792000 299.440000 316.080000 ;
    END
  END dbg_halt_req
  PIN dbg_resume_req
    DIRECTION INPUT ;
    USE SIGNAL ;
    PORT
      LAYER M7 ;
        RECT 296.432000 315.792000 296.560000 316.080000 ;
    END
  END dbg_resume_req
  PIN dbg_halted
    DIRECTION OUTPUT ;
    USE SIGNAL ;
    PORT
      LAYER M7 ;
        RECT 293.552000 315.792000 293.680000 316.080000 ;
    END
  END dbg_halted
  PIN dbg_reg_read_addr[15]
    DIRECTION INPUT ;
    USE SIGNAL ;
    PORT
      LAYER M7 ;
        RECT 290.384000 315.792000 290.512000 316.080000 ;
    END
  END dbg_reg_read_addr[15]
  PIN dbg_reg_read_addr[14]
    DIRECTION INPUT ;
    USE SIGNAL ;
    PORT
      LAYER M7 ;
        RECT 287.504000 315.792000 287.632000 316.080000 ;
    END
  END dbg_reg_read_addr[14]
  PIN dbg_reg_read_addr[13]
    DIRECTION INPUT ;
    USE SIGNAL ;
    PORT
      LAYER M7 ;
        RECT 284.336000 315.792000 284.464000 316.080000 ;
    END
  END dbg_reg_read_addr[13]
  PIN dbg_reg_read_addr[12]
    DIRECTION INPUT ;
    USE SIGNAL ;
    PORT
      LAYER M7 ;
        RECT 281.456000 315.792000 281.584000 316.080000 ;
    END
  END dbg_reg_read_addr[12]
  PIN dbg_reg_read_addr[11]
    DIRECTION INPUT ;
    USE SIGNAL ;
    PORT
      LAYER M7 ;
        RECT 278.576000 315.792000 278.704000 316.080000 ;
    END
  END dbg_reg_read_addr[11]
  PIN dbg_reg_read_addr[10]
    DIRECTION INPUT ;
    USE SIGNAL ;
    PORT
      LAYER M7 ;
        RECT 275.408000 315.792000 275.536000 316.080000 ;
    END
  END dbg_reg_read_addr[10]
  PIN dbg_reg_read_addr[9]
    DIRECTION INPUT ;
    USE SIGNAL ;
    PORT
      LAYER M7 ;
        RECT 272.528000 315.792000 272.656000 316.080000 ;
    END
  END dbg_reg_read_addr[9]
  PIN dbg_reg_read_addr[8]
    DIRECTION INPUT ;
    USE SIGNAL ;
    PORT
      LAYER M7 ;
        RECT 269.360000 315.792000 269.488000 316.080000 ;
    END
  END dbg_reg_read_addr[8]
  PIN dbg_reg_read_addr[7]
    DIRECTION INPUT ;
    USE SIGNAL ;
    PORT
      LAYER M7 ;
        RECT 266.480000 315.792000 266.608000 316.080000 ;
    END
  END dbg_reg_read_addr[7]
  PIN dbg_reg_read_addr[6]
    DIRECTION INPUT ;
    USE SIGNAL ;
    PORT
      LAYER M7 ;
        RECT 263.312000 315.792000 263.440000 316.080000 ;
    END
  END dbg_reg_read_addr[6]
  PIN dbg_reg_read_addr[5]
    DIRECTION INPUT ;
    USE SIGNAL ;
    PORT
      LAYER M7 ;
        RECT 260.432000 315.792000 260.560000 316.080000 ;
    END
  END dbg_reg_read_addr[5]
  PIN dbg_reg_read_addr[4]
    DIRECTION INPUT ;
    USE SIGNAL ;
    PORT
      LAYER M7 ;
        RECT 257.552000 315.792000 257.680000 316.080000 ;
    END
  END dbg_reg_read_addr[4]
  PIN dbg_reg_read_addr[3]
    DIRECTION INPUT ;
    USE SIGNAL ;
    PORT
      LAYER M7 ;
        RECT 254.384000 315.792000 254.512000 316.080000 ;
    END
  END dbg_reg_read_addr[3]
  PIN dbg_reg_read_addr[2]
    DIRECTION INPUT ;
    USE SIGNAL ;
    PORT
      LAYER M7 ;
        RECT 251.504000 315.792000 251.632000 316.080000 ;
    END
  END dbg_reg_read_addr[2]
  PIN dbg_reg_read_addr[1]
    DIRECTION INPUT ;
    USE SIGNAL ;
    PORT
      LAYER M7 ;
        RECT 248.336000 315.792000 248.464000 316.080000 ;
    END
  END dbg_reg_read_addr[1]
  PIN dbg_reg_read_addr[0]
    DIRECTION INPUT ;
    USE SIGNAL ;
    PORT
      LAYER M7 ;
        RECT 245.456000 315.792000 245.584000 316.080000 ;
    END
  END dbg_reg_read_addr[0]
  PIN dbg_reg_read_data[31]
    DIRECTION OUTPUT ;
    USE SIGNAL ;
    PORT
      LAYER M7 ;
        RECT 242.576000 315.792000 242.704000 316.080000 ;
    END
  END dbg_reg_read_data[31]
  PIN dbg_reg_read_data[30]
    DIRECTION OUTPUT ;
    USE SIGNAL ;
    PORT
      LAYER M7 ;
        RECT 239.408000 315.792000 239.536000 316.080000 ;
    END
  END dbg_reg_read_data[30]
  PIN dbg_reg_read_data[29]
    DIRECTION OUTPUT ;
    USE SIGNAL ;
    PORT
      LAYER M7 ;
        RECT 236.528000 315.792000 236.656000 316.080000 ;
    END
  END dbg_reg_read_data[29]
  PIN dbg_reg_read_data[28]
    DIRECTION OUTPUT ;
    USE SIGNAL ;
    PORT
      LAYER M7 ;
        RECT 233.360000 315.792000 233.488000 316.080000 ;
    END
  END dbg_reg_read_data[28]
  PIN dbg_reg_read_data[27]
    DIRECTION OUTPUT ;
    USE SIGNAL ;
    PORT
      LAYER M7 ;
        RECT 230.480000 315.792000 230.608000 316.080000 ;
    END
  END dbg_reg_read_data[27]
  PIN dbg_reg_read_data[26]
    DIRECTION OUTPUT ;
    USE SIGNAL ;
    PORT
      LAYER M7 ;
        RECT 227.600000 315.792000 227.728000 316.080000 ;
    END
  END dbg_reg_read_data[26]
  PIN dbg_reg_read_data[25]
    DIRECTION OUTPUT ;
    USE SIGNAL ;
    PORT
      LAYER M7 ;
        RECT 224.432000 315.792000 224.560000 316.080000 ;
    END
  END dbg_reg_read_data[25]
  PIN dbg_reg_read_data[24]
    DIRECTION OUTPUT ;
    USE SIGNAL ;
    PORT
      LAYER M7 ;
        RECT 221.552000 315.792000 221.680000 316.080000 ;
    END
  END dbg_reg_read_data[24]
  PIN dbg_reg_read_data[23]
    DIRECTION OUTPUT ;
    USE SIGNAL ;
    PORT
      LAYER M7 ;
        RECT 218.384000 315.792000 218.512000 316.080000 ;
    END
  END dbg_reg_read_data[23]
  PIN dbg_reg_read_data[22]
    DIRECTION OUTPUT ;
    USE SIGNAL ;
    PORT
      LAYER M7 ;
        RECT 215.504000 315.792000 215.632000 316.080000 ;
    END
  END dbg_reg_read_data[22]
  PIN dbg_reg_read_data[21]
    DIRECTION OUTPUT ;
    USE SIGNAL ;
    PORT
      LAYER M7 ;
        RECT 212.336000 315.792000 212.464000 316.080000 ;
    END
  END dbg_reg_read_data[21]
  PIN dbg_reg_read_data[20]
    DIRECTION OUTPUT ;
    USE SIGNAL ;
    PORT
      LAYER M7 ;
        RECT 209.456000 315.792000 209.584000 316.080000 ;
    END
  END dbg_reg_read_data[20]
  PIN dbg_reg_read_data[19]
    DIRECTION OUTPUT ;
    USE SIGNAL ;
    PORT
      LAYER M7 ;
        RECT 206.576000 315.792000 206.704000 316.080000 ;
    END
  END dbg_reg_read_data[19]
  PIN dbg_reg_read_data[18]
    DIRECTION OUTPUT ;
    USE SIGNAL ;
    PORT
      LAYER M7 ;
        RECT 203.408000 315.792000 203.536000 316.080000 ;
    END
  END dbg_reg_read_data[18]
  PIN dbg_reg_read_data[17]
    DIRECTION OUTPUT ;
    USE SIGNAL ;
    PORT
      LAYER M7 ;
        RECT 200.528000 315.792000 200.656000 316.080000 ;
    END
  END dbg_reg_read_data[17]
  PIN dbg_reg_read_data[16]
    DIRECTION OUTPUT ;
    USE SIGNAL ;
    PORT
      LAYER M7 ;
        RECT 197.360000 315.792000 197.488000 316.080000 ;
    END
  END dbg_reg_read_data[16]
  PIN dbg_reg_read_data[15]
    DIRECTION OUTPUT ;
    USE SIGNAL ;
    PORT
      LAYER M7 ;
        RECT 194.480000 315.792000 194.608000 316.080000 ;
    END
  END dbg_reg_read_data[15]
  PIN dbg_reg_read_data[14]
    DIRECTION OUTPUT ;
    USE SIGNAL ;
    PORT
      LAYER M7 ;
        RECT 191.600000 315.792000 191.728000 316.080000 ;
    END
  END dbg_reg_read_data[14]
  PIN dbg_reg_read_data[13]
    DIRECTION OUTPUT ;
    USE SIGNAL ;
    PORT
      LAYER M7 ;
        RECT 188.432000 315.792000 188.560000 316.080000 ;
    END
  END dbg_reg_read_data[13]
  PIN dbg_reg_read_data[12]
    DIRECTION OUTPUT ;
    USE SIGNAL ;
    PORT
      LAYER M7 ;
        RECT 185.552000 315.792000 185.680000 316.080000 ;
    END
  END dbg_reg_read_data[12]
  PIN dbg_reg_read_data[11]
    DIRECTION OUTPUT ;
    USE SIGNAL ;
    PORT
      LAYER M7 ;
        RECT 182.384000 315.792000 182.512000 316.080000 ;
    END
  END dbg_reg_read_data[11]
  PIN dbg_reg_read_data[10]
    DIRECTION OUTPUT ;
    USE SIGNAL ;
    PORT
      LAYER M7 ;
        RECT 179.504000 315.792000 179.632000 316.080000 ;
    END
  END dbg_reg_read_data[10]
  PIN dbg_reg_read_data[9]
    DIRECTION OUTPUT ;
    USE SIGNAL ;
    PORT
      LAYER M7 ;
        RECT 176.336000 315.792000 176.464000 316.080000 ;
    END
  END dbg_reg_read_data[9]
  PIN dbg_reg_read_data[8]
    DIRECTION OUTPUT ;
    USE SIGNAL ;
    PORT
      LAYER M7 ;
        RECT 173.456000 315.792000 173.584000 316.080000 ;
    END
  END dbg_reg_read_data[8]
  PIN dbg_reg_read_data[7]
    DIRECTION OUTPUT ;
    USE SIGNAL ;
    PORT
      LAYER M7 ;
        RECT 170.576000 315.792000 170.704000 316.080000 ;
    END
  END dbg_reg_read_data[7]
  PIN dbg_reg_read_data[6]
    DIRECTION OUTPUT ;
    USE SIGNAL ;
    PORT
      LAYER M7 ;
        RECT 167.408000 315.792000 167.536000 316.080000 ;
    END
  END dbg_reg_read_data[6]
  PIN dbg_reg_read_data[5]
    DIRECTION OUTPUT ;
    USE SIGNAL ;
    PORT
      LAYER M7 ;
        RECT 164.528000 315.792000 164.656000 316.080000 ;
    END
  END dbg_reg_read_data[5]
  PIN dbg_reg_read_data[4]
    DIRECTION OUTPUT ;
    USE SIGNAL ;
    PORT
      LAYER M7 ;
        RECT 161.360000 315.792000 161.488000 316.080000 ;
    END
  END dbg_reg_read_data[4]
  PIN dbg_reg_read_data[3]
    DIRECTION OUTPUT ;
    USE SIGNAL ;
    PORT
      LAYER M7 ;
        RECT 158.480000 315.792000 158.608000 316.080000 ;
    END
  END dbg_reg_read_data[3]
  PIN dbg_reg_read_data[2]
    DIRECTION OUTPUT ;
    USE SIGNAL ;
    PORT
      LAYER M7 ;
        RECT 155.600000 315.792000 155.728000 316.080000 ;
    END
  END dbg_reg_read_data[2]
  PIN dbg_reg_read_data[1]
    DIRECTION OUTPUT ;
    USE SIGNAL ;
    PORT
      LAYER M7 ;
        RECT 152.432000 315.792000 152.560000 316.080000 ;
    END
  END dbg_reg_read_data[1]
  PIN dbg_reg_read_data[0]
    DIRECTION OUTPUT ;
    USE SIGNAL ;
    PORT
      LAYER M7 ;
        RECT 149.552000 315.792000 149.680000 316.080000 ;
    END
  END dbg_reg_read_data[0]
  PIN dbg_reg_write_en
    DIRECTION INPUT ;
    USE SIGNAL ;
    PORT
      LAYER M7 ;
        RECT 146.384000 315.792000 146.512000 316.080000 ;
    END
  END dbg_reg_write_en
  PIN dbg_reg_write_addr[15]
    DIRECTION INPUT ;
    USE SIGNAL ;
    PORT
      LAYER M7 ;
        RECT 143.504000 315.792000 143.632000 316.080000 ;
    END
  END dbg_reg_write_addr[15]
  PIN dbg_reg_write_addr[14]
    DIRECTION INPUT ;
    USE SIGNAL ;
    PORT
      LAYER M7 ;
        RECT 140.624000 315.792000 140.752000 316.080000 ;
    END
  END dbg_reg_write_addr[14]
  PIN dbg_reg_write_addr[13]
    DIRECTION INPUT ;
    USE SIGNAL ;
    PORT
      LAYER M7 ;
        RECT 137.456000 315.792000 137.584000 316.080000 ;
    END
  END dbg_reg_write_addr[13]
  PIN dbg_reg_write_addr[12]
    DIRECTION INPUT ;
    USE SIGNAL ;
    PORT
      LAYER M7 ;
        RECT 134.576000 315.792000 134.704000 316.080000 ;
    END
  END dbg_reg_write_addr[12]
  PIN dbg_reg_write_addr[11]
    DIRECTION INPUT ;
    USE SIGNAL ;
    PORT
      LAYER M7 ;
        RECT 131.408000 315.792000 131.536000 316.080000 ;
    END
  END dbg_reg_write_addr[11]
  PIN dbg_reg_write_addr[10]
    DIRECTION INPUT ;
    USE SIGNAL ;
    PORT
      LAYER M7 ;
        RECT 128.528000 315.792000 128.656000 316.080000 ;
    END
  END dbg_reg_write_addr[10]
  PIN dbg_reg_write_addr[9]
    DIRECTION INPUT ;
    USE SIGNAL ;
    PORT
      LAYER M7 ;
        RECT 125.360000 315.792000 125.488000 316.080000 ;
    END
  END dbg_reg_write_addr[9]
  PIN dbg_reg_write_addr[8]
    DIRECTION INPUT ;
    USE SIGNAL ;
    PORT
      LAYER M7 ;
        RECT 122.480000 315.792000 122.608000 316.080000 ;
    END
  END dbg_reg_write_addr[8]
  PIN dbg_reg_write_addr[7]
    DIRECTION INPUT ;
    USE SIGNAL ;
    PORT
      LAYER M7 ;
        RECT 119.600000 315.792000 119.728000 316.080000 ;
    END
  END dbg_reg_write_addr[7]
  PIN dbg_reg_write_addr[6]
    DIRECTION INPUT ;
    USE SIGNAL ;
    PORT
      LAYER M7 ;
        RECT 116.432000 315.792000 116.560000 316.080000 ;
    END
  END dbg_reg_write_addr[6]
  PIN dbg_reg_write_addr[5]
    DIRECTION INPUT ;
    USE SIGNAL ;
    PORT
      LAYER M7 ;
        RECT 113.552000 315.792000 113.680000 316.080000 ;
    END
  END dbg_reg_write_addr[5]
  PIN dbg_reg_write_addr[4]
    DIRECTION INPUT ;
    USE SIGNAL ;
    PORT
      LAYER M7 ;
        RECT 110.384000 315.792000 110.512000 316.080000 ;
    END
  END dbg_reg_write_addr[4]
  PIN dbg_reg_write_addr[3]
    DIRECTION INPUT ;
    USE SIGNAL ;
    PORT
      LAYER M7 ;
        RECT 107.504000 315.792000 107.632000 316.080000 ;
    END
  END dbg_reg_write_addr[3]
  PIN dbg_reg_write_addr[2]
    DIRECTION INPUT ;
    USE SIGNAL ;
    PORT
      LAYER M7 ;
        RECT 104.624000 315.792000 104.752000 316.080000 ;
    END
  END dbg_reg_write_addr[2]
  PIN dbg_reg_write_addr[1]
    DIRECTION INPUT ;
    USE SIGNAL ;
    PORT
      LAYER M7 ;
        RECT 101.456000 315.792000 101.584000 316.080000 ;
    END
  END dbg_reg_write_addr[1]
  PIN dbg_reg_write_addr[0]
    DIRECTION INPUT ;
    USE SIGNAL ;
    PORT
      LAYER M7 ;
        RECT 98.576000 315.792000 98.704000 316.080000 ;
    END
  END dbg_reg_write_addr[0]
  PIN dbg_reg_write_data[31]
    DIRECTION INPUT ;
    USE SIGNAL ;
    PORT
      LAYER M7 ;
        RECT 95.408000 315.792000 95.536000 316.080000 ;
    END
  END dbg_reg_write_data[31]
  PIN dbg_reg_write_data[30]
    DIRECTION INPUT ;
    USE SIGNAL ;
    PORT
      LAYER M7 ;
        RECT 92.528000 315.792000 92.656000 316.080000 ;
    END
  END dbg_reg_write_data[30]
  PIN dbg_reg_write_data[29]
    DIRECTION INPUT ;
    USE SIGNAL ;
    PORT
      LAYER M7 ;
        RECT 89.360000 315.792000 89.488000 316.080000 ;
    END
  END dbg_reg_write_data[29]
  PIN dbg_reg_write_data[28]
    DIRECTION INPUT ;
    USE SIGNAL ;
    PORT
      LAYER M7 ;
        RECT 86.480000 315.792000 86.608000 316.080000 ;
    END
  END dbg_reg_write_data[28]
  PIN dbg_reg_write_data[27]
    DIRECTION INPUT ;
    USE SIGNAL ;
    PORT
      LAYER M7 ;
        RECT 83.600000 315.792000 83.728000 316.080000 ;
    END
  END dbg_reg_write_data[27]
  PIN dbg_reg_write_data[26]
    DIRECTION INPUT ;
    USE SIGNAL ;
    PORT
      LAYER M7 ;
        RECT 80.432000 315.792000 80.560000 316.080000 ;
    END
  END dbg_reg_write_data[26]
  PIN dbg_reg_write_data[25]
    DIRECTION INPUT ;
    USE SIGNAL ;
    PORT
      LAYER M7 ;
        RECT 77.552000 315.792000 77.680000 316.080000 ;
    END
  END dbg_reg_write_data[25]
  PIN dbg_reg_write_data[24]
    DIRECTION INPUT ;
    USE SIGNAL ;
    PORT
      LAYER M7 ;
        RECT 74.384000 315.792000 74.512000 316.080000 ;
    END
  END dbg_reg_write_data[24]
  PIN dbg_reg_write_data[23]
    DIRECTION INPUT ;
    USE SIGNAL ;
    PORT
      LAYER M7 ;
        RECT 71.504000 315.792000 71.632000 316.080000 ;
    END
  END dbg_reg_write_data[23]
  PIN dbg_reg_write_data[22]
    DIRECTION INPUT ;
    USE SIGNAL ;
    PORT
      LAYER M7 ;
        RECT 68.624000 315.792000 68.752000 316.080000 ;
    END
  END dbg_reg_write_data[22]
  PIN dbg_reg_write_data[21]
    DIRECTION INPUT ;
    USE SIGNAL ;
    PORT
      LAYER M7 ;
        RECT 65.456000 315.792000 65.584000 316.080000 ;
    END
  END dbg_reg_write_data[21]
  PIN dbg_reg_write_data[20]
    DIRECTION INPUT ;
    USE SIGNAL ;
    PORT
      LAYER M7 ;
        RECT 62.576000 315.792000 62.704000 316.080000 ;
    END
  END dbg_reg_write_data[20]
  PIN dbg_reg_write_data[19]
    DIRECTION INPUT ;
    USE SIGNAL ;
    PORT
      LAYER M7 ;
        RECT 59.408000 315.792000 59.536000 316.080000 ;
    END
  END dbg_reg_write_data[19]
  PIN dbg_reg_write_data[18]
    DIRECTION INPUT ;
    USE SIGNAL ;
    PORT
      LAYER M7 ;
        RECT 56.528000 315.792000 56.656000 316.080000 ;
    END
  END dbg_reg_write_data[18]
  PIN dbg_reg_write_data[17]
    DIRECTION INPUT ;
    USE SIGNAL ;
    PORT
      LAYER M7 ;
        RECT 53.648000 315.792000 53.776000 316.080000 ;
    END
  END dbg_reg_write_data[17]
  PIN dbg_reg_write_data[16]
    DIRECTION INPUT ;
    USE SIGNAL ;
    PORT
      LAYER M7 ;
        RECT 50.480000 315.792000 50.608000 316.080000 ;
    END
  END dbg_reg_write_data[16]
  PIN dbg_reg_write_data[15]
    DIRECTION INPUT ;
    USE SIGNAL ;
    PORT
      LAYER M7 ;
        RECT 47.600000 315.792000 47.728000 316.080000 ;
    END
  END dbg_reg_write_data[15]
  PIN dbg_reg_write_data[14]
    DIRECTION INPUT ;
    USE SIGNAL ;
    PORT
      LAYER M7 ;
        RECT 44.432000 315.792000 44.560000 316.080000 ;
    END
  END dbg_reg_write_data[14]
  PIN dbg_reg_write_data[13]
    DIRECTION INPUT ;
    USE SIGNAL ;
    PORT
      LAYER M7 ;
        RECT 41.552000 315.792000 41.680000 316.080000 ;
    END
  END dbg_reg_write_data[13]
  PIN dbg_reg_write_data[12]
    DIRECTION INPUT ;
    USE SIGNAL ;
    PORT
      LAYER M7 ;
        RECT 38.384000 315.792000 38.512000 316.080000 ;
    END
  END dbg_reg_write_data[12]
  PIN dbg_reg_write_data[11]
    DIRECTION INPUT ;
    USE SIGNAL ;
    PORT
      LAYER M7 ;
        RECT 35.504000 315.792000 35.632000 316.080000 ;
    END
  END dbg_reg_write_data[11]
  PIN dbg_reg_write_data[10]
    DIRECTION INPUT ;
    USE SIGNAL ;
    PORT
      LAYER M7 ;
        RECT 32.624000 315.792000 32.752000 316.080000 ;
    END
  END dbg_reg_write_data[10]
  PIN dbg_reg_write_data[9]
    DIRECTION INPUT ;
    USE SIGNAL ;
    PORT
      LAYER M7 ;
        RECT 29.456000 315.792000 29.584000 316.080000 ;
    END
  END dbg_reg_write_data[9]
  PIN dbg_reg_write_data[8]
    DIRECTION INPUT ;
    USE SIGNAL ;
    PORT
      LAYER M7 ;
        RECT 26.576000 315.792000 26.704000 316.080000 ;
    END
  END dbg_reg_write_data[8]
  PIN dbg_reg_write_data[7]
    DIRECTION INPUT ;
    USE SIGNAL ;
    PORT
      LAYER M7 ;
        RECT 23.408000 315.792000 23.536000 316.080000 ;
    END
  END dbg_reg_write_data[7]
  PIN dbg_reg_write_data[6]
    DIRECTION INPUT ;
    USE SIGNAL ;
    PORT
      LAYER M7 ;
        RECT 20.528000 315.792000 20.656000 316.080000 ;
    END
  END dbg_reg_write_data[6]
  PIN dbg_reg_write_data[5]
    DIRECTION INPUT ;
    USE SIGNAL ;
    PORT
      LAYER M7 ;
        RECT 17.648000 315.792000 17.776000 316.080000 ;
    END
  END dbg_reg_write_data[5]
  PIN dbg_reg_write_data[4]
    DIRECTION INPUT ;
    USE SIGNAL ;
    PORT
      LAYER M7 ;
        RECT 14.480000 315.792000 14.608000 316.080000 ;
    END
  END dbg_reg_write_data[4]
  PIN dbg_reg_write_data[3]
    DIRECTION INPUT ;
    USE SIGNAL ;
    PORT
      LAYER M7 ;
        RECT 11.600000 315.792000 11.728000 316.080000 ;
    END
  END dbg_reg_write_data[3]
  PIN dbg_reg_write_data[2]
    DIRECTION INPUT ;
    USE SIGNAL ;
    PORT
      LAYER M7 ;
        RECT 8.432000 315.792000 8.560000 316.080000 ;
    END
  END dbg_reg_write_data[2]
  PIN dbg_reg_write_data[1]
    DIRECTION INPUT ;
    USE SIGNAL ;
    PORT
      LAYER M7 ;
        RECT 5.552000 315.792000 5.680000 316.080000 ;
    END
  END dbg_reg_write_data[1]
  PIN dbg_reg_write_data[0]
    DIRECTION INPUT ;
    USE SIGNAL ;
    PORT
      LAYER M7 ;
        RECT 2.384000 315.792000 2.512000 316.080000 ;
    END
  END dbg_reg_write_data[0]
  PIN VDD
    DIRECTION INOUT ;
    USE POWER ;
    PORT
      LAYER M9 ;
        RECT 2.928000 2.928000 3.568000 3.568000 ;
    END
  END VDD
  PIN VSS
    DIRECTION INOUT ;
    USE GROUND ;
    PORT
      LAYER M9 ;
        RECT 1.968000 1.968000 2.608000 2.608000 ;
    END
  END VSS
  OBS
    LAYER M1 ;
      RECT 0.000000 0.000000 316.944000 316.080000 ;
    LAYER M2 ;
      RECT 0.000000 0.000000 316.944000 316.080000 ;
    LAYER M3 ;
      RECT 0.000000 0.000000 316.944000 316.080000 ;
    LAYER M4 ;
      RECT 0.000000 0.000000 316.944000 316.080000 ;
    LAYER M5 ;
      RECT 0.000000 0.000000 316.944000 316.080000 ;
    LAYER M6 ;
      RECT 0.000000 0.000000 316.944000 316.080000 ;
    LAYER M7 ;
      RECT 0.000000 0.000000 316.944000 316.080000 ;
    LAYER M8 ;
      RECT 0.000000 0.000000 316.944000 316.080000 ;
    LAYER M9 ;
      RECT 0.000000 0.000000 316.944000 316.080000 ;
    LAYER Pad ;
      RECT 0.000000 0.000000 316.944000 316.080000 ;
  END
END riscv_pipeline

END LIBRARY
